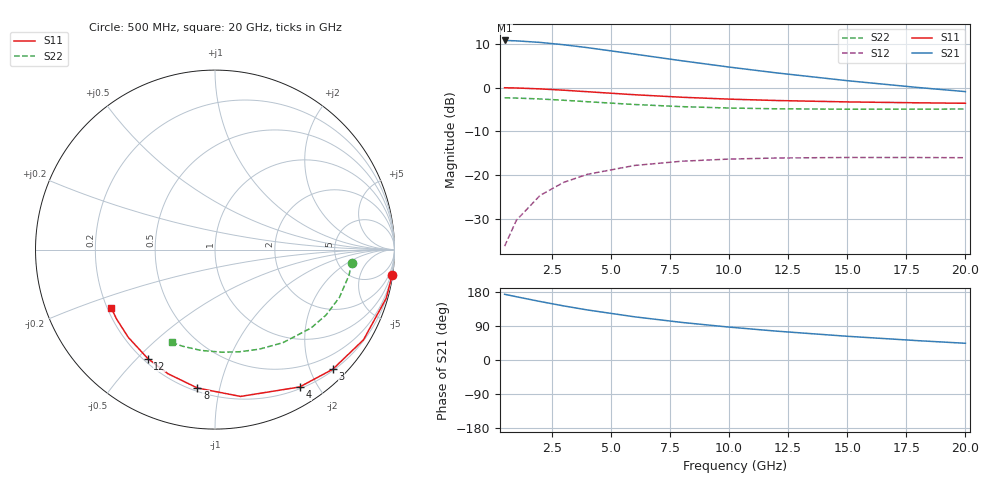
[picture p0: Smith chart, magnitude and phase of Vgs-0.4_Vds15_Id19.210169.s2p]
# Hz S RI R 50
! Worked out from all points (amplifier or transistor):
!   12 points, 500 MHz to 20 GHz, reference 50 ohm
!   highest |S21| = 10.8 dB at 500 MHz (marker M1)
!   |S21| within 3 dB of that: start of sweep to 5.833 GHz
!   unconditionally stable (mu >= 1): 17.34 GHz to end of sweep
!   at 2 GHz: K = 0.10, MSG = 17.5 dB, |S12| = -24.6 dB
!   at 8 GHz: K = 0.43, MSG = 11.5 dB, |S12| = -16.8 dB
!   at 20 GHz: K = 1.19, MAG = 4.9 dB, |S12| = -16.0 dB
!   S11 on the Smith chart (normalised r, x): 500 MHz: 0, -14; 3 GHz: 0.22, -2.37; 4 GHz: 0.22, -1.77; 8 GHz: 0.22, -0.86; 12 GHz: 0.22, -0.54; 20 GHz: 0.22, -0.25
5e8  0.9881 -0.139  -3.44 0.3954  0.00148 0.0154  0.7618 -0.0719
1e9  0.9534 -0.2721  -3.337 0.7734  0.00581 0.03  0.7471 -0.1415
2e9  0.8278 -0.5021  -2.966 1.421  0.0214 0.0546  0.6934 -0.2662
3e9  0.656 -0.6668  -2.462 1.872  0.0426 0.0709  0.6186 -0.3646
4e9  0.4711 -0.7655  -1.923 2.127  0.0652 0.0788  0.5358 -0.4365
6e9  0.142 -0.8181  -0.9813 2.208  0.104 0.0766  0.3779 -0.5189
8e9  -0.0981 -0.771  -0.3225 2.003  0.1302 0.0624  0.2454 -0.555
1e10  -0.2621 -0.6915  0.096 1.717  0.1459 0.0453  0.136 -0.5692
1.2e10  -0.3742 -0.6071  0.3521 1.433  0.1544 0.0287  0.0423 -0.5718
1.5e10  -0.4825 -0.4896  0.553 1.067  0.1592 0.00722  -0.0784 -0.5617
1.8e10  -0.5483 -0.3871  0.6317 0.7802  0.1588 -0.01  -0.1815 -0.5381
2e10  -0.5777 -0.3262  0.6474 0.6274  0.1572 -0.0195  -0.2419 -0.5163
